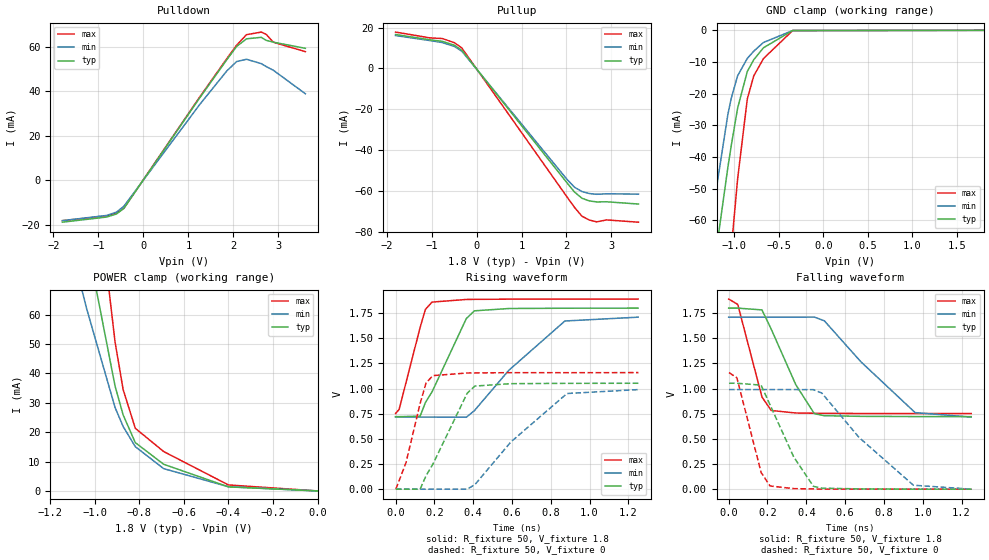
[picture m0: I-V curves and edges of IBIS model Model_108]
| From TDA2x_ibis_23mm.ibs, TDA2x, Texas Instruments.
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| Model based on original model for DDR_SEIOPB_H
|   Sub model SR111_DRV34_1P8
[model]   Model_108
|[Description]  [1.8V-I/O-X-X]
|   , ,
|[Input Load]
|[Output Drive]
|Voltage   1.8V
|Mode   I/O
Model_type   I/O
Polarity   Non-Inverting
Enable   Active-Low
Vinl =  0.775
Vinh =  1.025
Cref =  15.0000pF
Rref =  100.0000M
Vref =  0V
Vmeas =  0.9
C_comp   2p   2p   2p
[Model Spec]
Vinl   0.78   0.735   0.825
Vinh   1.02   0.975   1.065
[Receiver Thresholds]
Tslew_ac = 0.5n
Vth= 0.9
Vth_max= 0.945
Vth_min= 0.81
Vinh_ac= 0.2
Vinh_dc= 0.125
Vinl_ac= -0.2
Vinl_dc= -0.125
[Temperature Range]   25   125   -40
[Voltage Range]   1.8   1.71   1.89
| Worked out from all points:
|   slope of the pulldown table from 0 to 0.27 V, typ, clamps not added: 33.3 ohm
|   slope of the pullup table from 0 to 0.27 V, typ, clamps not added: 35.5 ohm
|   GND clamp passes 1 mA (typ) near -0.48 V on its own axis
|   POWER clamp passes 1 mA (typ) near -0.38 V on its own axis
|   rising waveform, R_fixture 50, V_fixture 1.8: 20-80 % time 172ps typ, 369ps min, 90.1ps max; typ from 0.721 V to 1.8 V
|   rising waveform, R_fixture 50, V_fixture 0: 20-80 % time 172ps typ, 367ps min, 89.3ps max; typ from 0 V to 1.05 V
|   falling waveform, R_fixture 50, V_fixture 1.8: 20-80 % time 157ps typ, 329ps min, 88.6ps max; typ from 1.8 V to 0.721 V
|   falling waveform, R_fixture 50, V_fixture 0: 20-80 % time 162ps typ, 340ps min, 88.6ps max; typ from 1.05 V to 0 V
[POWER_clamp]
-1.8V     464.6mA    344.4mA    740.8mA
-1.273V   197mA      143.3mA    314.4mA
-1.164V   144mA      104.2mA    229mA
-1.145V   135.3mA    97.86mA    215mA
-1.055V   93.25mA    67.59mA    146.5mA
-1.036V   85.18mA    61.89mA    133.3mA
-909.1mV  35.72mA    28.41mA    50.73mA
-872.7mV  25.87mA    21.94mA    34.5mA
-818.2mV  16.45mA    15.08mA    21.33mA
-690.9mV  9.084mA    7.592mA    13.42mA
-400mV    1.38mA     1.43mA     2.039mA
0V        227.3nA    761nA      1.176uA
[Pulldown]
-1.8V     -18.96mA   -18.25mA   -18.29mA
-818.2mV  -16.64mA   -15.93mA   -16.11mA
-600mV    -15.26mA   -14.42mA   -14.86mA
-436.4mV  -12.77mA   -11.85mA   -12.76mA
1.255V    37.14mA    34.14mA    37.53mA
1.855V    54.25mA    49.2mA     54.74mA
2.073V    60.22mA    53.41mA    60.8mA
2.291V    63.64mA    54.44mA    65.5mA
2.618V    64.32mA    52.48mA    66.68mA
2.727V    62.98mA    51.19mA    65.69mA
2.891V    62.13mA    49.45mA    62.08mA
3.6V      59.37mA    38.9mA     57.88mA
[Pullup]
-1.8V     16.66mA    16.14mA    17.84mA
-1.036V   14.05mA    13.69mA    15mA
-763.6mV  13.33mA    12.72mA    14.68mA
-490.9mV  11.4mA     10.78mA    12.65mA
-327.3mV  8.923mA    8.488mA    10.05mA
2.018V    -56.27mA   -54.56mA   -63.19mA
2.182V    -60.67mA   -58.29mA   -68.22mA
2.345V    -63.65mA   -60.35mA   -72.46mA
2.509V    -64.94mA   -61.33mA   -74.33mA
2.673V    -65.44mA   -61.69mA   -75.21mA
2.891V    -65.36mA   -61.45mA   -74.26mA
3.6V      -66.47mA   -61.61mA   -75.37mA
[GND_clamp]
-1.8V     -200.8mA   -187.9mA   -345.9mA
-1.327V   -95.75mA   -76.22mA   -171.1mA
-1.255V   -80.19mA   -60.47mA   -144.9mA
-1.218V   -72.53mA   -52.92mA   -131.9mA
-1.073V   -43.32mA   -26.59mA   -81.54mA
-1.036V   -36.61mA   -21.6mA    -69.55mA
-963.6mV  -24.61mA   -14.37mA   -47.01mA
-854.5mV  -12.98mA   -8.864mA   -21.66mA
-781.8mV  -9.263mA   -6.573mA   -14.36mA
-672.7mV  -5.498mA   -3.827mA   -8.897mA
-345.5mV  -48.81uA   -73.08uA   -79.37uA
1.8V      227.3nA    3.986uA    988nA
[Ramp]
dV/dt_f 0.64819116/0.15732551n 0.59696121/0.329717n  0.68332087/88.701046p
dV/dt_r 0.63301156/0.17256637n 0.59531836/0.36728602n 0.69620168/89.53648p
R_load = 50
[Rising Waveform]
R_fixture = 50
V_fixture = 1.8
V_fixture_min = 1.71
V_fixture_max = 1.89
0s        720.8mV    716.7mV    752.7mV
18.38ps   720.9mV    716.6mV    792.5mV
126.7ps   725.8mV    716.6mV    1.608V
154ps     862mV      716.6mV    1.788V
188.5ps   969mV      716.7mV    1.86V
364.7ps   1.696V     715mV      1.886V
406.5ps   1.773V     781.1mV    1.887V
583.3ps   1.796V     1.181V     1.889V
872.7ps   1.799V     1.672V     1.89V
1.25ns    1.8V       1.71V      1.89V
[Rising Waveform]
R_fixture = 50
V_fixture = 0
V_fixture_min = 0
V_fixture_max = 0
1.558ps   0V         0V         0V
53.63ps   0V         0V         261.6mV
126.7ps   0V         0V         852mV
157.1ps   133.2mV    0V         1.055V
192.1ps   247.2mV    0V         1.129V
369.1ps   953.6mV    0V         1.155V
408.7ps   1.025V     44.57mV    1.156V
594.1ps   1.049V     469.1mV    1.158V
883.6ps   1.052V     951mV      1.158V
1.252ns   1.053V     990.1mV    1.159V
[Falling Waveform]
R_fixture = 50
V_fixture = 1.8
V_fixture_min = 1.71
V_fixture_max = 1.89
0s        1.8V       1.71V      1.89V
46.64ps   1.8V       1.71V      1.837V
171.6ps   1.782V     1.71V      916.2mV
219.3ps   1.591V     1.71V      782.2mV
345.6ps   1.04V      1.71V      757.3mV
441.3ps   750.7mV    1.711V     754.7mV
492.9ps   730.5mV    1.674V     753.9mV
681.1ps   723.9mV    1.267V     752.4mV
960.8ps   721.8mV    761.1mV    751.9mV
1.25ns    720.8mV    716.7mV    751.8mV
[Falling Waveform]
R_fixture = 50
V_fixture = 0
V_fixture_min = 0
V_fixture_max = 0
1.558ps   1.053V     990.1mV    1.159V
42.33ps   1.053V     990.1mV    1.107V
167.2ps   1.034V     990.1mV    165.9mV
213.4ps   837.4mV    990mV      31.64mV
335.6ps   318.8mV    989.8mV    5.172mV
436.8ps   28.22mV    989.4mV    2.215mV
480.2ps   10.24mV    955.2mV    0V
671.6ps   2.641mV    514.7mV    0V
952.2ps   0V         39.18mV    0V
1.252ns   0V         0V         0V
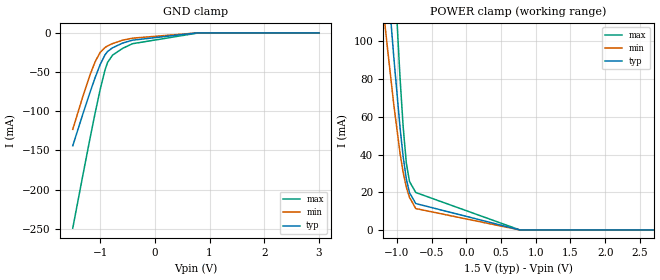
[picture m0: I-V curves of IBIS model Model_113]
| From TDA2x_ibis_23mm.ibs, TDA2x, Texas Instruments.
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| Model based on original model for DDR_SEIOPB_H
|   Sub model DDR3_ODT_120_1P5
[model]   Model_113
|[Description]  [1.5V-INPUT-X-X]
|   , ,
|[Input Load]
|[Output Drive]
|Voltage   1.5V
|Mode   INPUT
Model_type   Input
Polarity   Non-Inverting
Vinl = 0.65
Vinh = 0.85
C_comp   1p   0.5p   1.75p
[Receiver Thresholds]
Tslew_ac = 0.5n
Vth= 0.75
Vth_max= 0.7875
Vth_min= 0.675
Vinh_ac= 0.175
Vinh_dc= 0.1
Vinl_ac= -0.175
Vinl_dc= -0.1
[Temperature Range]   25   125   -40
[Voltage Range]   1.5   1.425   1.575
[POWER_clamp]
-1.5V     313.5mA    230.7mA    499.5mA
-1.273V   199.8mA    145.4mA    317.8mA
-1.182V   155.6mA    112.6mA    246.7mA
-1.136V   133.9mA    96.79mA    211.7mA
-1.045V   92.18mA    66.78mA    143.6mA
-954.5mV  54.51mA    40.82mA    81.12mA
-909.1mV  38.89mA    30.54mA    54.77mA
-863.6mV  27.13mA    22.75mA    35.57mA
-818.2mV  19.83mA    17.32mA    25.73mA
-727.3mV  14.01mA    11.35mA    19.86mA
772.7mV   0A         0A         0A
3V        0A         0A         0A
[GND_clamp]
-1.5V     -144mA     -123.1mA   -249.1mA
-1.318V   -104.1mA   -81.62mA   -182.5mA
-1.182V   -75.27mA   -53.07mA   -133.7mA
-1.091V   -57.04mA   -36.82mA   -102.3mA
-1V       -40.52mA   -24.95mA   -72.54mA
-909.1mV  -27.83mA   -18.53mA   -46.98mA
-863.6mV  -23.8mA    -16.61mA   -37.72mA
-772.7mV  -19.02mA   -13.67mA   -28.41mA
-590.9mV  -13.06mA   -9.333mA   -19.82mA
-409.1mV  -9.294mA   -6.738mA   -13.81mA
772.7mV   0A         0A         -328.7uA
3V        0A         0A         0A
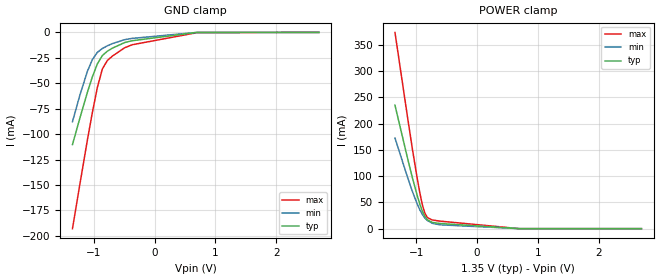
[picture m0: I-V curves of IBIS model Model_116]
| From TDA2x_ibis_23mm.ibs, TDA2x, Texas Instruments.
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| Model based on original model for DDR_SEIOPB_H
|   Sub model DDR3L_ODT_120_1P35
[model]   Model_116
|[Description]  [1.35V-INPUT-X-X]
|   , ,
|[Input Load]
|[Output Drive]
|Voltage   1.35V
|Mode   INPUT
Model_type   Input
Polarity   Non-Inverting
Vinl = 0.585
Vinh = 0.765
C_comp   1p   0.5p   1.75p
[Receiver Thresholds]
Tslew_ac = 5n
Vth= 0.675
Vth_max= 0.709
Vth_min= 0.608
Vinh_ac= 0.175
Vinh_dc= 0.1
Vinl_ac= -0.175
Vinl_dc= -0.1
[Temperature Range]   25   125   -40
[Voltage Range]   1.35   1.2825   1.4175
[POWER_clamp]
-1.35V    235.2mA    172.7mA    373.9mA
-1.145V   135mA      98.41mA    213.4mA
-1.064V   97.08mA    70.95mA    151.9mA
-981.8mV  61.96mA    46.31mA    94.02mA
-940.9mV  46.38mA    35.8mA     67.88mA
-900mV    33.1mA     27.05mA    45.49mA
-859.1mV  23.18mA    20.38mA    29.5mA
-818.2mV  16.93mA    15.6mA     21.23mA
-736.4mV  11.84mA    10.12mA    16.5mA
-613.6mV  9.897mA    7.359mA    14.38mA
695.5mV   0A         0A         26.81uA
2.7V      0A         0A         0A
[GND_clamp]
-1.35V    -110.3mA   -87.86mA   -193mA
-1.227V   -84.01mA   -61.44mA   -148.8mA
-1.105V   -58.98mA   -38.34mA   -105.9mA
-1.023V   -43.7mA    -26.73mA   -78.71mA
-940.9mV  -30.94mA   -19.63mA   -54.14mA
-859.1mV  -22.78mA   -15.82mA   -35.96mA
-777.3mV  -18.52mA   -13.21mA   -27.69mA
-695.5mV  -15.53mA   -11.04mA   -23.38mA
-490.9mV  -9.942mA   -7.113mA   -15.05mA
-368.2mV  -8.2mA     -5.879mA   -12.14mA
695.5mV   0A         0A         -267.5uA
2.7V      0A         0A         0A
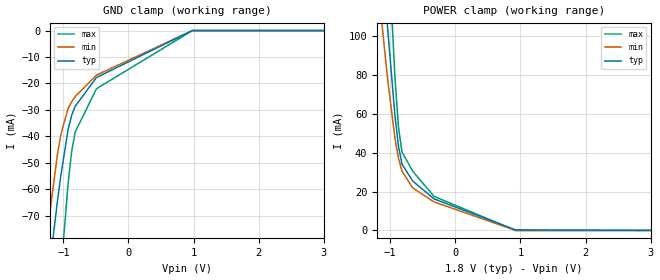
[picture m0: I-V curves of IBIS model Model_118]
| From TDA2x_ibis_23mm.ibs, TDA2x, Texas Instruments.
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| Model based on original model for DDR_SEIOPB_H
|   Sub model DDR2_ODT_80_1P8
[model]   Model_118
|[Description]  [1.8V-INPUT-X-X]
|   , ,
|[Input Load]
|[Output Drive]
|Voltage   1.8V
|Mode   INPUT
Model_type   Input
Polarity   Non-Inverting
Vinl =  0.775
Vinh =  1.025
C_comp   1p   0.5p   1.75p
[Receiver Thresholds]
Tslew_ac = 0.5n
Vth= 0.9
Vth_max= 0.945
Vth_min= 0.81
Vinh_ac= 0.2
Vinh_dc= 0.125
Vinl_ac= -0.2
Vinl_dc= -0.125
[Temperature Range]   25   125   -40
[Voltage Range]   1.8   1.71   1.89
[POWER_clamp]
-1.8V     482.4mA    357.9mA    759.4mA
-1.255V   205.7mA    151.4mA    318.3mA
-1.145V   152.9mA    112.8mA    233.2mA
-1.091V   127.3mA    94.41mA    191.7mA
-1.036V   102.6mA    76.98mA    151.4mA
-927.3mV  59.11mA    47.51mA    78.99mA
-872.7mV  43.45mA    37.29mA    53.09mA
-818.2mV  34.12mA    30.5mA     40.26mA
-654.5mV  25.4mA     21.91mA    30.49mA
-327.3mV  16.24mA    14.7mA     17.54mA
927.3mV   295.1uA    0A         0A
3.6V      0A         0A         0A
[GND_clamp]
-1.8V     -219.3mA   -205.9mA   -368.7mA
-1.364V   -121.8mA   -102mA     -206.3mA
-1.309V   -110mA     -89.84mA   -186.4mA
-1.255V   -98.27mA   -78.06mA   -166.7mA
-1.091V   -64.72mA   -46.91mA   -109.1mA
-1.036V   -54.5mA    -39.11mA   -90.88mA
-927.3mV  -37.55mA   -29.51mA   -58.13mA
-872.7mV  -32.11mA   -26.95mA   -45.87mA
-818.2mV  -28.67mA   -24.98mA   -38.4mA
-490.9mV  -17.74mA   -16.84mA   -21.99mA
981.8mV   0A         0A         0A
3.6V      0A         0A         0A
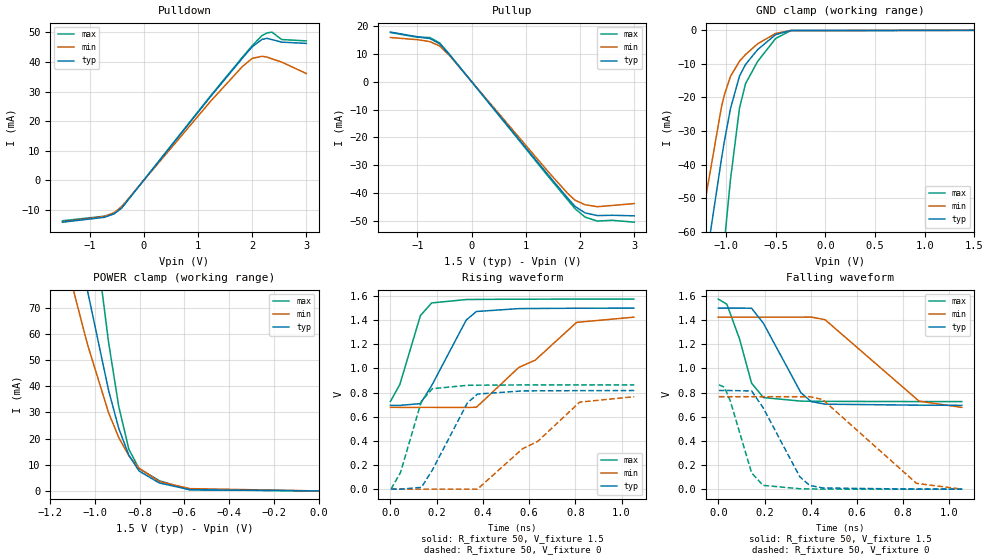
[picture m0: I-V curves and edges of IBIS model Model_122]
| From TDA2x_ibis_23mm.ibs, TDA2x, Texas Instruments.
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| Model based on original model for DDR_SEIOPB_H
|   Sub model SR101_DRV40_1P5
[model]   Model_122
|[Description]  [1.5V-I/O-X-X]
|   , ,
|[Input Load]
|[Output Drive]
|Voltage   1.5V
|Mode   I/O
Model_type   I/O
Polarity   Non-Inverting
Enable   Active-Low
Vinl =  0.65
Vinh =  0.85
Cref =  15.0000pF
Rref =  100.0000M
Vref =  0V
Vmeas =  0.75
C_comp   2p   2p   2p
[Model Spec]
Vinl   0.65   0.6125   0.6875
Vinh   0.85   0.8125   0.8875
[Receiver Thresholds]
Tslew_ac = 0.5n
Vth= 0.75
Vth_max= 0.7875
Vth_min= 0.675
Vinh_ac= 0.175
Vinh_dc= 0.1
Vinl_ac= -0.175
Vinl_dc= -0.1
[Temperature Range]   25   125   -40
[Voltage Range]   1.5   1.425   1.575
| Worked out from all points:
|   slope of the pulldown table from 0 to 0.225 V, typ, clamps not added: 43 ohm
|   slope of the pullup table from 0 to 0.225 V, typ, clamps not added: 41.7 ohm
|   GND clamp passes 1 mA (typ) near -0.48 V on its own axis
|   POWER clamp passes 1 mA (typ) near -0.62 V on its own axis
|   rising waveform, R_fixture 50, V_fixture 1.5: 20-80 % time 136ps typ, 308ps min, 78.1ps max; typ from 0.695 V to 1.5 V
|   rising waveform, R_fixture 50, V_fixture 0: 20-80 % time 135ps typ, 299ps min, 78ps max; typ from 0 V to 0.817 V
|   falling waveform, R_fixture 50, V_fixture 1.5: 20-80 % time 134ps typ, 278ps min, 77.5ps max; typ from 1.5 V to 0.695 V
|   falling waveform, R_fixture 50, V_fixture 0: 20-80 % time 135ps typ, 288ps min, 77.9ps max; typ from 0.817 V to 0 V
[POWER_clamp]
-1.5V     302.8mA    223.9mA    484.4mA
-1.242V   174.3mA    127.3mA    279.1mA
-1.136V   123.3mA    89.68mA    196.8mA
-1.045V   81.65mA    59.62mA    128.8mA
-1.03V    75mA       54.92mA    117.8mA
-939.4mV  38.44mA    29.91mA    56.84mA
-893.9mV  23.93mA    20.41mA    32.31mA
-848.5mV  13.61mA    13.43mA    15.91mA
-803mV    7.623mA    8.663mA    8.564mA
-712.1mV  3.022mA    3.561mA    3.877mA
-575.8mV  470.5uA    872uA      449uA
0V        112.6nA    435.6nA    613.8nA
[Pulldown]
-1.5V     -14.18mA   -14.05mA   -13.7mA
-727.3mV  -12.54mA   -12.27mA   -12.15mA
-545.5mV  -11.35mA   -10.95mA   -11.1mA
-409.1mV  -9.378mA   -8.925mA   -9.416mA
1.227V    28.16mA    26.58mA    28.43mA
1.818V    41.23mA    38.42mA    41.56mA
2V        45.11mA    41.2mA     45.49mA
2.182V    47.62mA    41.92mA    48.94mA
2.273V    47.99mA    41.65mA    49.78mA
2.364V    47.57mA    41.06mA    50.1mA
2.545V    46.7mA     39.96mA    47.58mA
3V        46.28mA    36.09mA    47.12mA
[Pullup]
-1.5V     17.97mA    16.01mA    17.82mA
-1V       16.28mA    15.23mA    16.1mA
-772.7mV  15.66mA    14.54mA    16.02mA
-590.9mV  13.75mA    12.97mA    14.08mA
-409.1mV  9.799mA    9.534mA    9.955mA
1.409V    -33.42mA   -32.26mA   -33.94mA
1.773V    -41.87mA   -40.19mA   -42.52mA
1.909V    -44.87mA   -42.6mA    -45.68mA
2.091V    -47.15mA   -44.23mA   -48.65mA
2.318V    -48.13mA   -44.93mA   -50.11mA
2.591V    -48.02mA   -44.49mA   -49.82mA
3V        -48.22mA   -43.8mA    -50.51mA
[GND_clamp]
-1.5V     -133.6mA   -115.7mA   -234.3mA
-1.288V   -87.29mA   -67.59mA   -156.8mA
-1.197V   -68.11mA   -48.64mA   -124.4mA
-1.045V   -38.25mA   -22.77mA   -72.51mA
-1.015V   -32.88mA   -19.1mA    -62.74mA
-954.5mV  -23.3mA    -13.72mA   -44.4mA
-863.6mV  -13.6mA    -9.192mA   -23.11mA
-803mV    -10.18mA   -7.193mA   -15.89mA
-681.8mV  -5.771mA   -4.027mA   -9.287mA
-500mV    -1.264mA   -914.7uA   -2.429mA
-348.5mV  -52.39uA   -75.11uA   -85.87uA
1.5V      112.6nA    528.1nA    514.5nA
[Ramp]
dV/dt_f 0.48371638/0.1344601n 0.44929255/0.27899089n 0.51008323/77.587251p
dV/dt_r 0.49174227/0.13539252n 0.46153752/0.30103568n 0.51970717/78.162105p
R_load = 50
[Rising Waveform]
R_fixture = 50
V_fixture = 1.5
V_fixture_min = 1.425
V_fixture_max = 1.575
0s        694.7mV    677.7mV    726.3mV
40.92ps   694mV      677.6mV    867.3mV
129.9ps   708.9mV    677.6mV    1.438V
178.6ps   858.2mV    677.7mV    1.543V
328ps     1.401V     676.8mV    1.571V
372.1ps   1.472V     678.6mV    1.572V
555.7ps   1.496V     1.009V     1.574V
626.7ps   1.497V     1.069V     1.574V
805.6ps   1.499V     1.382V     1.575V
1.053ns   1.5V       1.425V     1.575V
[Rising Waveform]
R_fixture = 50
V_fixture = 0
V_fixture_min = 0
V_fixture_max = 0
2.617ps   0V         0V         0V
43.65ps   0V         0V         137.9mV
134.3ps   15.11mV    0V         728.9mV
181.2ps   156.8mV    0V         832.2mV
332.5ps   712.7mV    0V         860.5mV
376.6ps   787.9mV    0V         861.5mV
571.4ps   814.1mV    334.9mV    863.4mV
636.5ps   814.9mV    394.4mV    863.6mV
819ps     816.1mV    721.2mV    863.9mV
1.055ns   817.1mV    766.1mV    864.1mV
[Falling Waveform]
R_fixture = 50
V_fixture = 1.5
V_fixture_min = 1.425
V_fixture_max = 1.575
0s        1.5V       1.425V     1.575V
37ps      1.5V       1.425V     1.532V
91.62ps   1.5V       1.425V     1.246V
144ps     1.499V     1.425V     877.9mV
195.5ps   1.373V     1.425V     758.8mV
357.2ps   799.6mV    1.425V     729.5mV
401.2ps   726mV      1.426V     728.5mV
461.8ps   704.2mV    1.404V     727.5mV
868.6ps   695.8mV    728.9mV    725.6mV
1.053ns   694.7mV    677.7mV    725.4mV
[Falling Waveform]
R_fixture = 50
V_fixture = 0
V_fixture_min = 0
V_fixture_max = 0
2.617ps   817.1mV    766.1mV    864.1mV
26.17ps   817.2mV    766.1mV    845.5mV
51.72ps   817.2mV    766.1mV    731.9mV
144.1ps   813.5mV    766.2mV    135mV
193.2ps   677.1mV    766.1mV    31.72mV
352.5ps   102.6mV    766mV      3.47mV
395.2ps   31.13mV    766.5mV    2.395mV
451.1ps   10.07mV    742.9mV    0V
857.4ps   0V         48.03mV    0V
1.055ns   0V         0V         0V
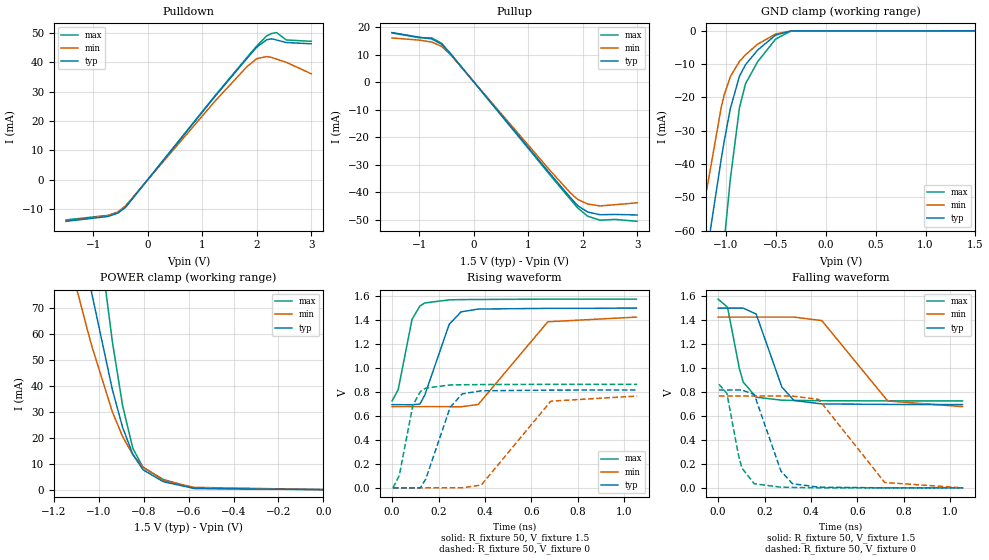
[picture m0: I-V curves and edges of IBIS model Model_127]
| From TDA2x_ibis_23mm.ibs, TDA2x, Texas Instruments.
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| Model based on original model for DDR_SEIOPB_H
|   Sub model SR000_DRV40_1P5
[model]   Model_127
|[Description]  [1.5V-I/O-X-X]
|   , ,
|[Input Load]
|[Output Drive]
|Voltage   1.5V
|Mode   I/O
Model_type   I/O
Polarity   Non-Inverting
Enable   Active-Low
Vinl =  0.65
Vinh =  0.85
Cref =  15.0000pF
Rref =  100.0000M
Vref =  0V
Vmeas =  0.75
C_comp   2p   2p   2p
[Model Spec]
Vinl   0.65   0.6125   0.6875
Vinh   0.85   0.8125   0.8875
[Receiver Thresholds]
Tslew_ac = 0.5n
Vth= 0.75
Vth_max= 0.7875
Vth_min= 0.675
Vinh_ac= 0.175
Vinh_dc= 0.1
Vinl_ac= -0.175
Vinl_dc= -0.1
[Temperature Range]   25   125   -40
[Voltage Range]   1.5   1.425   1.575
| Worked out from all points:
|   slope of the pulldown table from 0 to 0.225 V, typ, clamps not added: 43 ohm
|   slope of the pullup table from 0 to 0.225 V, typ, clamps not added: 41.7 ohm
|   GND clamp passes 1 mA (typ) near -0.48 V on its own axis
|   POWER clamp passes 1 mA (typ) near -0.62 V on its own axis
|   rising waveform, R_fixture 50, V_fixture 1.5: 20-80 % time 82.9ps typ, 189ps min, 50.6ps max; typ from 0.695 V to 1.5 V
|   rising waveform, R_fixture 50, V_fixture 0: 20-80 % time 83ps typ, 185ps min, 50.5ps max; typ from 0 V to 0.817 V
|   falling waveform, R_fixture 50, V_fixture 1.5: 20-80 % time 83.7ps typ, 176ps min, 52.3ps max; typ from 1.5 V to 0.695 V
|   falling waveform, R_fixture 50, V_fixture 0: 20-80 % time 83.6ps typ, 179ps min, 51.7ps max; typ from 0.817 V to 0 V
[POWER_clamp]
-1.5V     302.8mA    223.9mA    484.4mA
-1.242V   174.3mA    127.3mA    279.1mA
-1.136V   123.3mA    89.68mA    196.8mA
-1.045V   81.65mA    59.62mA    128.8mA
-1.03V    75mA       54.92mA    117.8mA
-939.4mV  38.44mA    29.91mA    56.84mA
-893.9mV  23.93mA    20.41mA    32.31mA
-848.5mV  13.61mA    13.43mA    15.91mA
-803mV    7.623mA    8.663mA    8.564mA
-712.1mV  3.022mA    3.561mA    3.877mA
-575.8mV  470.5uA    872uA      449uA
0V        112.6nA    435.6nA    613.8nA
[Pulldown]
-1.5V     -14.18mA   -14.05mA   -13.7mA
-727.3mV  -12.54mA   -12.27mA   -12.15mA
-545.5mV  -11.35mA   -10.95mA   -11.1mA
-409.1mV  -9.378mA   -8.925mA   -9.416mA
1.227V    28.16mA    26.58mA    28.43mA
1.818V    41.23mA    38.42mA    41.56mA
2V        45.11mA    41.2mA     45.49mA
2.182V    47.62mA    41.92mA    48.94mA
2.273V    47.99mA    41.65mA    49.78mA
2.364V    47.57mA    41.06mA    50.1mA
2.545V    46.7mA     39.96mA    47.58mA
3V        46.28mA    36.09mA    47.12mA
[Pullup]
-1.5V     17.97mA    16.01mA    17.82mA
-1V       16.28mA    15.23mA    16.1mA
-772.7mV  15.66mA    14.54mA    16.02mA
-590.9mV  13.75mA    12.97mA    14.08mA
-409.1mV  9.799mA    9.534mA    9.955mA
1.409V    -33.42mA   -32.26mA   -33.94mA
1.773V    -41.87mA   -40.19mA   -42.52mA
1.909V    -44.87mA   -42.6mA    -45.68mA
2.091V    -47.15mA   -44.23mA   -48.65mA
2.318V    -48.13mA   -44.93mA   -50.11mA
2.591V    -48.02mA   -44.49mA   -49.82mA
3V        -48.22mA   -43.8mA    -50.51mA
[GND_clamp]
-1.5V     -133.6mA   -115.7mA   -234.3mA
-1.288V   -87.29mA   -67.59mA   -156.8mA
-1.197V   -68.11mA   -48.64mA   -124.4mA
-1.045V   -38.25mA   -22.77mA   -72.51mA
-1.015V   -32.88mA   -19.1mA    -62.74mA
-954.5mV  -23.3mA    -13.72mA   -44.4mA
-863.6mV  -13.6mA    -9.192mA   -23.11mA
-803mV    -10.18mA   -7.193mA   -15.89mA
-681.8mV  -5.771mA   -4.027mA   -9.287mA
-500mV    -1.264mA   -914.7uA   -2.429mA
-348.5mV  -52.39uA   -75.11uA   -85.87uA
1.5V      112.6nA    528.1nA    514.5nA
[Ramp]
dV/dt_f 0.48364903/83.821371p 0.44912812/0.17636424n 0.50998143/52.340509p
dV/dt_r 0.49180675/83.243552p 0.46129703/0.18594643n 0.51998788/50.619034p
R_load = 50
[Rising Waveform]
R_fixture = 50
V_fixture = 1.5
V_fixture_min = 1.425
V_fixture_max = 1.575
0s        694.7mV    677.7mV    726mV
26.2ps    694mV      677.6mV    819.5mV
86ps      693.6mV    677.6mV    1.407V
119.7ps   699.3mV    677.6mV    1.517V
140.8ps   774mV      677.6mV    1.543V
246.1ps   1.365V     677.4mV    1.569V
297.3ps   1.469V     676.9mV    1.571V
371.2ps   1.492V     696mV      1.572V
671ps     1.498V     1.386V     1.575V
1.053ns   1.5V       1.425V     1.575V
[Rising Waveform]
R_fixture = 50
V_fixture = 0
V_fixture_min = 0
V_fixture_max = 0
3.612ps   0V         0V         0V
30.99ps   0V         0V         103.4mV
89.21ps   0V         0V         688.8mV
122ps     0V         0V         803.5mV
144.9ps   72.96mV    0V         832.7mV
250.3ps   672.5mV    0V         858.6mV
302.1ps   784.8mV    0V         860.5mV
384.4ps   810mV      23.87mV    862mV
683.8ps   815.7mV    723.3mV    863.8mV
1.056ns   817.1mV    766.1mV    864.1mV
[Falling Waveform]
R_fixture = 50
V_fixture = 1.5
V_fixture_min = 1.425
V_fixture_max = 1.575
0s        1.5V       1.425V     1.575V
40.52ps   1.5V       1.425V     1.507V
91.44ps   1.5V       1.425V     996.8mV
107.8ps   1.5V       1.425V     883.5mV
163.8ps   1.451V     1.425V     756.6mV
274.7ps   841.1mV    1.425V     731.6mV
327ps     729mV      1.425V     729.6mV
446.7ps   700.5mV    1.396V     727.3mV
730.7ps   696.3mV    725mV      725.7mV
1.053ns   694.7mV    677.7mV    725.4mV
[Falling Waveform]
R_fixture = 50
V_fixture = 0
V_fixture_min = 0
V_fixture_max = 0
3.612ps   817.1mV    766.1mV    864.1mV
37.75ps   817.3mV    766.2mV    787.9mV
87.13ps   816.8mV    766.2mV    278.2mV
102.3ps   816.8mV    766.2mV    165.9mV
155.8ps   779.5mV    766.2mV    33.95mV
270.3ps   141.5mV    766.2mV    5.695mV
320.4ps   34.44mV    765.9mV    3.63mV
433.6ps   6.028mV    738.2mV    0V
718.1ps   0V         44.47mV    0V
1.056ns   0V         0V         0V
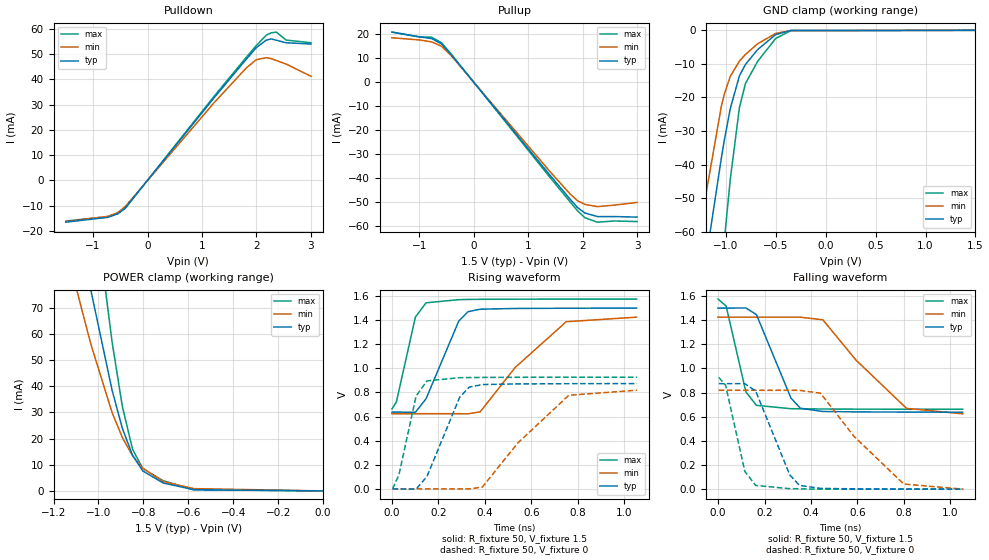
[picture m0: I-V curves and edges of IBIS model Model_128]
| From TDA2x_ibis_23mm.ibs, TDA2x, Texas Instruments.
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| Model based on original model for DDR_SEIOPB_H
|   Sub model SR011_DRV34_1P5
[model]   Model_128
|[Description]  [1.5V-I/O-X-X]
|   , ,
|[Input Load]
|[Output Drive]
|Voltage   1.5V
|Mode   I/O
Model_type   I/O
Polarity   Non-Inverting
Enable   Active-Low
Vinl =  0.65
Vinh =  0.85
Cref =  15.0000pF
Rref =  100.0000M
Vref =  0V
Vmeas =  0.75
C_comp   2p   2p   2p
[Model Spec]
Vinl   0.65   0.6125   0.6875
Vinh   0.85   0.8125   0.8875
[Receiver Thresholds]
Tslew_ac = 0.5n
Vth= 0.75
Vth_max= 0.7875
Vth_min= 0.675
Vinh_ac= 0.175
Vinh_dc= 0.1
Vinl_ac= -0.175
Vinl_dc= -0.1
[Temperature Range]   25   125   -40
[Voltage Range]   1.5   1.425   1.575
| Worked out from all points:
|   slope of the pulldown table from 0 to 0.225 V, typ, clamps not added: 36.8 ohm
|   slope of the pullup table from 0 to 0.225 V, typ, clamps not added: 35.8 ohm
|   GND clamp passes 1 mA (typ) near -0.48 V on its own axis
|   POWER clamp passes 1 mA (typ) near -0.62 V on its own axis
|   rising waveform, R_fixture 50, V_fixture 1.5: 20-80 % time 112ps typ, 267ps min, 61.5ps max; typ from 0.637 V to 1.5 V
|   rising waveform, R_fixture 50, V_fixture 0: 20-80 % time 111ps typ, 260ps min, 61.6ps max; typ from 0 V to 0.874 V
|   falling waveform, R_fixture 50, V_fixture 1.5: 20-80 % time 111ps typ, 245ps min, 62.9ps max; typ from 1.5 V to 0.637 V
|   falling waveform, R_fixture 50, V_fixture 0: 20-80 % time 111ps typ, 250ps min, 62.6ps max; typ from 0.874 V to 0 V
[POWER_clamp]
-1.5V     302.8mA    223.9mA    484.4mA
-1.242V   174.3mA    127.3mA    279.1mA
-1.136V   123.3mA    89.68mA    196.8mA
-1.045V   81.65mA    59.62mA    128.8mA
-1.03V    75mA       54.92mA    117.8mA
-939.4mV  38.44mA    29.91mA    56.84mA
-893.9mV  23.93mA    20.41mA    32.31mA
-848.5mV  13.61mA    13.43mA    15.91mA
-803mV    7.623mA    8.663mA    8.564mA
-712.1mV  3.022mA    3.561mA    3.877mA
-575.8mV  470.5uA    872uA      449uA
0V        112.6nA    435.6nA    613.8nA
[Pulldown]
-1.5V     -16.54mA   -16.32mA   -16.11mA
-727.3mV  -14.62mA   -14.26mA   -14.29mA
-545.5mV  -13.24mA   -12.72mA   -13.05mA
-409.1mV  -10.94mA   -10.36mA   -11.07mA
1.227V    32.84mA    30.87mA    33.41mA
1.818V    48.09mA    44.61mA    48.84mA
2V        52.62mA    47.82mA    53.46mA
2.182V    55.55mA    48.58mA    57.5mA
2.273V    55.99mA    48.2mA     58.42mA
2.364V    55.5mA     47.46mA    58.71mA
2.545V    54.48mA    46.06mA    55.55mA
3V        54mA       41.23mA    54.49mA
[Pullup]
-1.5V     20.96mA    18.6mA     20.95mA
-1V       19mA       17.69mA    18.93mA
-772.7mV  18.26mA    16.89mA    18.84mA
-590.9mV  16.04mA    15.07mA    16.54mA
-409.1mV  11.43mA    11.07mA    11.7mA
1.409V    -38.97mA   -37.46mA   -39.88mA
1.773V    -48.83mA   -46.66mA   -49.96mA
1.909V    -52.33mA   -49.44mA   -53.68mA
2.045V    -54.57mA   -50.97mA   -56.55mA
2.273V    -56.03mA   -51.89mA   -58.38mA
2.591V    -56.03mA   -51.23mA   -57.86mA
3V        -56.26mA   -50.14mA   -58.12mA
[GND_clamp]
-1.5V     -133.6mA   -115.7mA   -234.3mA
-1.288V   -87.29mA   -67.59mA   -156.8mA
-1.197V   -68.11mA   -48.64mA   -124.4mA
-1.045V   -38.25mA   -22.77mA   -72.51mA
-1.015V   -32.88mA   -19.1mA    -62.74mA
-954.5mV  -23.3mA    -13.72mA   -44.4mA
-863.6mV  -13.6mA    -9.192mA   -23.11mA
-803mV    -10.18mA   -7.193mA   -15.89mA
-681.8mV  -5.771mA   -4.027mA   -9.287mA
-500mV    -1.264mA   -914.7uA   -2.429mA
-348.5mV  -52.39uA   -75.11uA   -85.87uA
1.5V      112.6nA    528.1nA    514.5nA
[Ramp]
dV/dt_f 0.51822132/0.11075306n 0.48137328/0.24542701n  0.5480301/62.972467p
dV/dt_r 0.52633839/0.11136384n  0.4935113/0.26182759n  0.5577269/61.70354p
R_load = 50
[Rising Waveform]
R_fixture = 50
V_fixture = 1.5
V_fixture_min = 1.425
V_fixture_max = 1.575
0s        637.3mV    624.3mV    663.2mV
19.08ps   637mV      624.2mV    720.4mV
101ps     635.7mV    624.2mV    1.425V
147ps     748.1mV    624.2mV    1.544V
287.6ps   1.392V     624.2mV    1.57V
327.2ps   1.47V      622.6mV    1.572V
379.8ps   1.491V     639.3mV    1.573V
530.2ps   1.497V     1.007V     1.574V
750.2ps   1.499V     1.387V     1.575V
1.053ns   1.5V       1.425V     1.575V
[Rising Waveform]
R_fixture = 50
V_fixture = 0
V_fixture_min = 0
V_fixture_max = 0
2.72ps    0V         0V         0V
30.07ps   0V         0V         116mV
104.1ps   -2.032mV   0V         770.9mV
150.9ps   103.2mV    0V         896.2mV
291.3ps   759.2mV    0V         922.9mV
332.6ps   844.5mV    0V         923.9mV
389.1ps   865.8mV    15.05mV    924.8mV
542ps     871.3mV    381.5mV    926mV
761.3ps   873mV      776.8mV    926.6mV
1.055ns   874.1mV    819mV      926.7mV
[Falling Waveform]
R_fixture = 50
V_fixture = 1.5
V_fixture_min = 1.425
V_fixture_max = 1.575
0s        1.5V       1.425V     1.575V
34.81ps   1.5V       1.425V     1.517V
120ps     1.501V     1.425V     805.4mV
165.3ps   1.446V     1.425V     694.5mV
313.6ps   755.3mV    1.425V     666.7mV
354ps     670.5mV    1.425V     665.7mV
451.1ps   643.5mV    1.403V     664.1mV
593.4ps   640.3mV    1.07V      663mV
810.9ps   638.5mV    669.7mV    662.4mV
1.053ns   637.3mV    624.3mV    662.3mV
[Falling Waveform]
R_fixture = 50
V_fixture = 0
V_fixture_min = 0
V_fixture_max = 0
2.72ps    874.1mV    819mV      926.7mV
32.34ps   874.3mV    819.1mV    861.6mV
115.4ps   874.2mV    819.1mV    146.6mV
162ps     812.9mV    819mV      31.16mV
308.5ps   119.1mV    818.9mV    3.932mV
350.1ps   31.47mV    818.9mV    2.764mV
441.1ps   6.279mV    795.1mV    0V
584.7ps   2.691mV    438.3mV    0V
799.3ps   0V         42.46mV    0V
1.055ns   0V         0V         0V
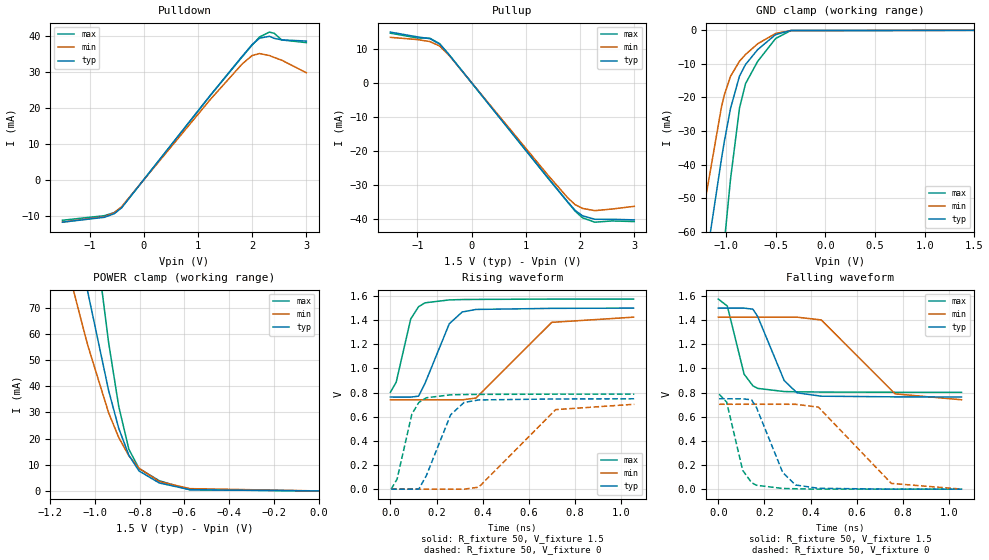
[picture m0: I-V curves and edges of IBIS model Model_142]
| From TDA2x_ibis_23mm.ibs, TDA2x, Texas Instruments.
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| Model based on original model for DDR_SEIOPB_H
|   Sub model SR001_DRV48_1P5
[model]   Model_142
|[Description]  [1.5V-I/O-X-X]
|   , ,
|[Input Load]
|[Output Drive]
|Voltage   1.5V
|Mode   I/O
Model_type   I/O
Polarity   Non-Inverting
Enable   Active-Low
Vinl =  0.65
Vinh =  0.85
Cref =  15.0000pF
Rref =  100.0000M
Vref =  0V
Vmeas =  0.75
C_comp   2p   2p   2p
[Model Spec]
Vinl   0.65   0.6125   0.6875
Vinh   0.85   0.8125   0.8875
[Receiver Thresholds]
Tslew_ac = 0.5n
Vth= 0.75
Vth_max= 0.7875
Vth_min= 0.675
Vinh_ac= 0.175
Vinh_dc= 0.1
Vinl_ac= -0.175
Vinl_dc= -0.1
[Temperature Range]   25   125   -40
[Voltage Range]   1.5   1.425   1.575
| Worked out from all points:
|   slope of the pulldown table from 0 to 0.225 V, typ, clamps not added: 51.5 ohm
|   slope of the pullup table from 0 to 0.225 V, typ, clamps not added: 50.1 ohm
|   GND clamp passes 1 mA (typ) near -0.48 V on its own axis
|   POWER clamp passes 1 mA (typ) near -0.62 V on its own axis
|   rising waveform, R_fixture 50, V_fixture 1.5: 20-80 % time 93ps typ, 229ps min, 56.2ps max; typ from 0.763 V to 1.5 V
|   rising waveform, R_fixture 50, V_fixture 0: 20-80 % time 93ps typ, 224ps min, 56.4ps max; typ from 0 V to 0.749 V
|   falling waveform, R_fixture 50, V_fixture 1.5: 20-80 % time 94.4ps typ, 212ps min, 58.3ps max; typ from 1.5 V to 0.763 V
|   falling waveform, R_fixture 50, V_fixture 0: 20-80 % time 94.2ps typ, 216ps min, 57.2ps max; typ from 0.749 V to 0 V
[POWER_clamp]
-1.5V     302.8mA    223.9mA    484.4mA
-1.242V   174.3mA    127.3mA    279.1mA
-1.136V   123.3mA    89.68mA    196.8mA
-1.045V   81.65mA    59.62mA    128.8mA
-1.03V    75mA       54.92mA    117.8mA
-939.4mV  38.44mA    29.91mA    56.84mA
-893.9mV  23.93mA    20.41mA    32.31mA
-848.5mV  13.61mA    13.43mA    15.91mA
-803mV    7.623mA    8.663mA    8.564mA
-712.1mV  3.022mA    3.561mA    3.877mA
-575.8mV  470.5uA    872uA      449uA
0V        112.6nA    435.6nA    613.8nA
[Pulldown]
-1.5V     -11.81mA   -11.79mA   -11.27mA
-727.3mV  -10.45mA   -10.3mA    -10mA
-545.5mV  -9.463mA   -9.189mA   -9.136mA
-409.1mV  -7.817mA   -7.49mA    -7.751mA
1.227V    23.47mA    22.31mA    23.4mA
1.818V    34.37mA    32.24mA    34.22mA
2V        37.61mA    34.55mA    37.45mA
2.136V    39.37mA    35.1mA     39.71mA
2.318V    39.9mA     34.55mA    41.07mA
2.409V    39.32mA    34mA       40.72mA
2.545V    38.91mA    33.26mA    38.88mA
3V        38.57mA    29.76mA    38.14mA
[Pullup]
-1.5V     14.98mA    13.43mA    14.66mA
-1V       13.57mA    12.78mA    13.25mA
-772.7mV  13.05mA    12.2mA     13.19mA
-590.9mV  11.46mA    10.89mA    11.59mA
-409.1mV  8.169mA    8.001mA    8.195mA
1.409V    -27.86mA   -27.07mA   -27.94mA
1.773V    -34.91mA   -33.72mA   -35mA
1.909V    -37.4mA    -35.72mA   -37.61mA
2.045V    -38.99mA   -36.82mA   -39.6mA
2.273V    -40.02mA   -37.48mA   -40.87mA
2.591V    -40.02mA   -37mA      -40.5mA
3V        -40.19mA   -36.21mA   -40.69mA
[GND_clamp]
-1.5V     -133.6mA   -115.7mA   -234.3mA
-1.288V   -87.29mA   -67.59mA   -156.8mA
-1.197V   -68.11mA   -48.64mA   -124.4mA
-1.045V   -38.25mA   -22.77mA   -72.51mA
-1.015V   -32.88mA   -19.1mA    -62.74mA
-954.5mV  -23.3mA    -13.72mA   -44.4mA
-863.6mV  -13.6mA    -9.192mA   -23.11mA
-803mV    -10.18mA   -7.193mA   -15.89mA
-681.8mV  -5.771mA   -4.027mA   -9.287mA
-500mV    -1.264mA   -914.7uA   -2.429mA
-348.5mV  -52.39uA   -75.11uA   -85.87uA
1.5V      112.6nA    528.1nA    514.5nA
[Ramp]
dV/dt_f  0.4424594/94.511921p 0.41132894/0.21290378n 0.46370359/58.357147p
dV/dt_r 0.45078989/93.298417p 0.42363717/0.22468686n 0.47383231/56.503683p
R_load = 50
[Rising Waveform]
R_fixture = 50
V_fixture = 1.5
V_fixture_min = 1.425
V_fixture_max = 1.575
0s        763.3mV    740.8mV    803.4mV
25ps      762.6mV    740.7mV    885.4mV
88.01ps   762.4mV    740.7mV    1.41V
122.2ps   770.9mV    740.7mV    1.512V
150.2ps   877.9mV    740.7mV    1.544V
255.2ps   1.371V     740.5mV    1.568V
311.1ps   1.468V     739.8mV    1.571V
370.7ps   1.489V     755.1mV    1.572V
698.8ps   1.498V     1.382V     1.575V
1.053ns   1.5V       1.425V     1.575V
[Rising Waveform]
R_fixture = 50
V_fixture = 0
V_fixture_min = 0
V_fixture_max = 0
3.404ps   0V         0V         0V
28.94ps   0V         0V         83.14mV
92.77ps   0V         0V         620.9mV
122.9ps   0V         0V         717.8mV
155.8ps   112.7mV    0V         757.5mV
261ps     616.6mV    0V         781.8mV
319.3ps   718.6mV    0V         783.9mV
382.6ps   739.3mV    16.46mV    785.2mV
715.6ps   747.4mV    659.1mV    787.1mV
1.056ns   748.7mV    703.3mV    787.3mV
[Falling Waveform]
R_fixture = 50
V_fixture = 1.5
V_fixture_min = 1.425
V_fixture_max = 1.575
0s        1.5V       1.425V     1.575V
39.05ps   1.5V       1.425V     1.517V
111.7ps   1.5V       1.425V     953.1mV
149.7ps   1.491V     1.425V     856.3mV
170.7ps   1.43V      1.425V     835mV
285.3ps   899.9mV    1.425V     808.8mV
340.6ps   798.4mV    1.425V     806.6mV
446ps     770.3mV    1.402V     804.6mV
765.4ps   764.8mV    789.6mV    802.8mV
1.053ns   763.3mV    740.8mV    802.5mV
[Falling Waveform]
R_fixture = 50
V_fixture = 0
V_fixture_min = 0
V_fixture_max = 0
3.404ps   748.7mV    703.3mV    787.3mV
36.15ps   748.9mV    703.3mV    721.2mV
105.5ps   748.4mV    703.3mV    156.4mV
144.1ps   740.2mV    703.4mV    53.92mV
165.3ps   676.1mV    703.3mV    32.35mV
278.8ps   138.7mV    703.3mV    5.736mV
334.2ps   34.7mV     703.1mV    3.405mV
433.2ps   7.152mV    680mV      0V
749.3ps   0V         47.56mV    0V
1.056ns   0V         0V         0V
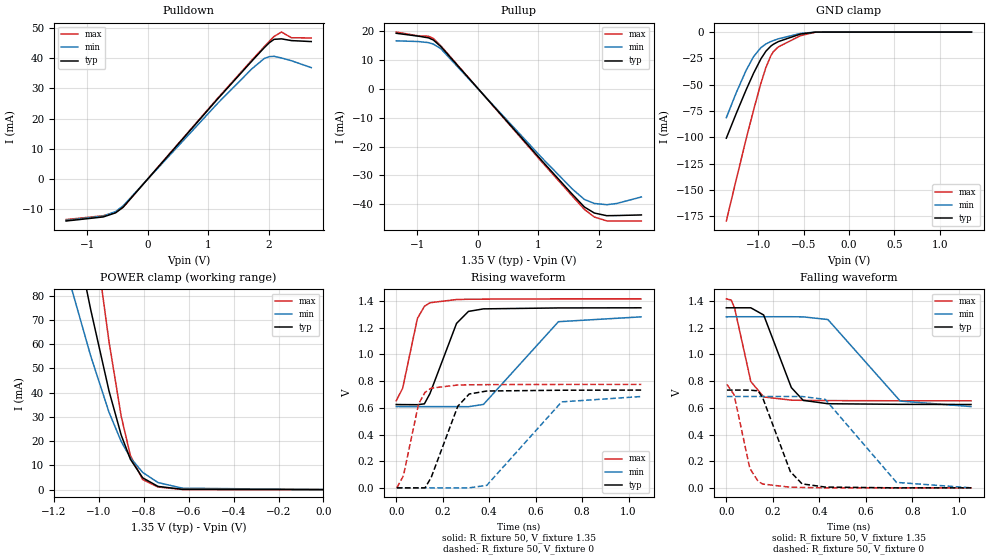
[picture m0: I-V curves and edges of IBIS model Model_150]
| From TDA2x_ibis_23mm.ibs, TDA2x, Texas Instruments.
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| Model based on original model for DDR_SEIOPB_H
|   Sub model SR001_DRV40_1P35
[model]   Model_150
|[Description]  [1.35V-I/O-X-X]
|   , ,
|[Input Load]
|[Output Drive]
|Voltage   1.35V
|Mode   I/O
Model_type   I/O
Polarity   Non-Inverting
Enable   Active-Low
Vinl =  0.585
Vinh =  0.765
Cref =  15.0000pF
Rref =  100.0000M
Vref =  0V
Vmeas =  0.675
C_comp   2p   2p   2p
[Model Spec]
Vinl   0.585   0.55125   0.61875
Vinh   0.765   0.73125   0.79875
[Receiver Thresholds]
Tslew_ac = 5n
Vth= 0.675
Vth_max= 0.709
Vth_min= 0.608
Vinh_ac= 0.175
Vinh_dc= 0.1
Vinl_ac= -0.175
Vinl_dc= -0.1
[Temperature Range]   25   125   -40
[Voltage Range]   1.35   1.2825   1.4175
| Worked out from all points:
|   slope of the pulldown table from 0 to 0.203 V, typ, clamps not added: 43 ohm
|   slope of the pullup table from 0 to 0.203 V, typ, clamps not added: 42 ohm
|   GND clamp passes 1 mA (typ) near -0.48 V on its own axis
|   POWER clamp passes 1 mA (typ) near -0.72 V on its own axis
|   rising waveform, R_fixture 50, V_fixture 1.35: 20-80 % time 91.2ps typ, 208ps min, 54.4ps max; typ from 0.625 V to 1.35 V
|   rising waveform, R_fixture 50, V_fixture 0: 20-80 % time 91.2ps typ, 202ps min, 54.1ps max; typ from 0 V to 0.733 V
|   falling waveform, R_fixture 50, V_fixture 1.35: 20-80 % time 91.3ps typ, 193ps min, 55.5ps max; typ from 1.35 V to 0.625 V
|   falling waveform, R_fixture 50, V_fixture 0: 20-80 % time 91.2ps typ, 197ps min, 55.2ps max; typ from 0.733 V to 0 V
[POWER_clamp]
-1.35V    224.4mA    165.8mA    358.5mA
-1.214V   157mA      115.5mA    250.8mA
-1.132V   117.8mA    86.59mA    187.7mA
-1.118V   111.4mA    81.92mA    177.3mA
-1.036V   74.26mA    55.16mA    116.8mA
-954.5mV  40.7mA     31.91mA    61.06mA
-900mV    22.42mA    19.79mA    30.14mA
-859.1mV  12.48mA    13.09mA    13.96mA
-804.5mV  4.85mA     7.084mA    4.132mA
-736.4mV  1.313mA    2.9mA      1.073mA
-627.3mV  101.6uA    577.3uA    45.9uA
0V        75.63nA    322.4nA    418.5nA
[Pulldown]
-1.35V    -13.93mA   -13.71mA   -13.45mA
-736.4mV  -12.58mA   -12.32mA   -12.19mA
-531.8mV  -11.22mA   -10.8mA    -10.99mA
-409.1mV  -9.378mA   -8.926mA   -9.416mA
1.145V    26.32mA    24.88mA    26.57mA
1.718V    39.05mA    36.49mA    39.37mA
1.923V    43.49mA    39.91mA    43.83mA
2.005V    45.12mA    40.54mA    45.58mA
2.086V    46.28mA    40.65mA    47.24mA
2.209V    46.44mA    40.1mA     48.7mA
2.373V    45.86mA    39.19mA    46.8mA
2.7V      45.54mA    36.91mA    46.74mA
[Pullup]
-1.35V    19.14mA    16.53mA    19.57mA
-981.8mV  18.13mA    16.28mA    18.23mA
-818.2mV  17.57mA    15.91mA    18.13mA
-736.4mV  16.82mA    15.4mA     17.33mA
-613.6mV  14.56mA    13.83mA    14.83mA
1.064V    -25.08mA   -24.06mA   -25.52mA
1.555V    -36.41mA   -34.6mA    -37.03mA
1.759V    -40.9mA    -38.29mA   -41.73mA
1.923V    -42.98mA   -39.67mA   -44.36mA
2.127V    -43.9mA    -40.1mA    -45.7mA
2.291V    -43.85mA   -39.69mA   -45.73mA
2.7V      -43.64mA   -37.43mA   -45.74mA
[GND_clamp]
-1.35V    -100.7mA   -81.27mA   -179.3mA
-1.241V   -77.31mA   -57.61mA   -140mA
-1.132V   -54.83mA   -36.31mA   -101.6mA
-1.05V    -39.08mA   -23.36mA   -74mA
-968.2mV  -25.28mA   -14.71mA   -48.34mA
-913.6mV  -18.13mA   -11.32mA   -33.52mA
-859.1mV  -13.28mA   -9.024mA   -22.35mA
-831.8mV  -11.61mA   -8.091mA   -18.64mA
-777.3mV  -9.078mA   -6.444mA   -14.07mA
-531.8mV  -1.871mA   -1.307mA   -3.441mA
-368.2mV  -88.76uA   -111.2uA   -158uA
1.35V     75.63nA    385.5nA    349.4nA
[Ramp]
dV/dt_f 0.43558262/91.40583p  0.40476929/0.19325305n 0.45930907/55.547329p
dV/dt_r 0.44168804/91.627517p 0.41292997/0.20360653n 0.46732083/54.369436p
R_load = 50
[Rising Waveform]
R_fixture = 50
V_fixture = 1.35
V_fixture_min = 1.2825
V_fixture_max = 1.4175
0s        624.9mV    609.4mV    653.1mV
27.79ps   624.2mV    609.3mV    746.8mV
91.18ps   623.5mV    609.3mV    1.27V
121.3ps   629.9mV    609.3mV    1.361V
145.1ps   706.4mV    609.3mV    1.388V
259.6ps   1.233V     609.2mV    1.412V
310.9ps   1.323V     608.3mV    1.414V
375.5ps   1.342V     625.6mV    1.415V
698.2ps   1.349V     1.246V     1.417V
1.053ns   1.35V      1.282V     1.417V
[Rising Waveform]
R_fixture = 50
V_fixture = 0
V_fixture_min = 0
V_fixture_max = 0
2.607ps   0V         0V         0V
31.2ps    0V         0V         91.09mV
95.89ps   0V         0V         628mV
124ps     0V         0V         716.1mV
150.3ps   76.77mV    0V         747.6mV
264.9ps   611.5mV    0V         771.2mV
314ps     703.5mV    0V         772.7mV
389.8ps   726.1mV    18.78mV    773.9mV
711.8ps   731.9mV    644.7mV    775.5mV
1.055ns   733mV      684.9mV    775.7mV
[Falling Waveform]
R_fixture = 50
V_fixture = 1.35
V_fixture_min = 1.2825
V_fixture_max = 1.4175
0s        1.35V      1.282V     1.417V
20.88ps   1.35V      1.283V     1.408V
35.66ps   1.35V      1.283V     1.348V
105.4ps   1.35V      1.283V     797mV
160.7ps   1.296V     1.283V     681.5mV
279.8ps   751.5mV    1.283V     657.7mV
330.8ps   656mV      1.282V     656.1mV
437.1ps   630.7mV    1.262V     654.2mV
748.3ps   626.2mV    650.7mV    652.7mV
1.053ns   624.9mV    609.4mV    652.5mV
[Falling Waveform]
R_fixture = 50
V_fixture = 0
V_fixture_min = 0
V_fixture_max = 0
2.607ps   733mV      684.9mV    775.7mV
33.13ps   733.2mV    685mV      698.6mV
101ps     732.8mV    685mV      146.5mV
136.9ps   727.2mV    685mV      48.51mV
156.9ps   673.5mV    685mV      28.46mV
275.3ps   122.3mV    685mV      4.697mV
325.9ps   29.81mV    684.8mV    2.976mV
425.7ps   5.882mV    663.1mV    0V
732.2ps   0V         40.9mV     0V
1.055ns   0V         0V         0V
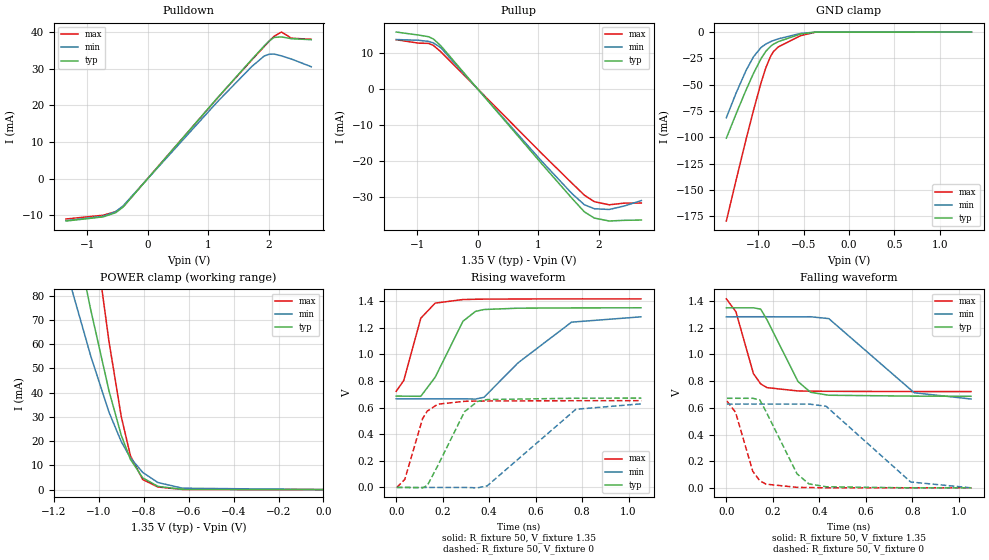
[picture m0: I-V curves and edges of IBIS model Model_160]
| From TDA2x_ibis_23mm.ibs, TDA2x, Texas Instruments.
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| Model based on original model for DDR_SEIOPB_H
|   Sub model SR011_DRV48_1P35
[model]   Model_160
|[Description]  [1.35V-I/O-X-X]
|   , ,
|[Input Load]
|[Output Drive]
|Voltage   1.35V
|Mode   I/O
Model_type   I/O
Polarity   Non-Inverting
Enable   Active-Low
Vinl =  0.585
Vinh =  0.765
Cref =  15.0000pF
Rref =  100.0000M
Vref =  0V
Vmeas =  0.675
C_comp   2p   2p   2p
[Model Spec]
Vinl   0.585   0.55125   0.61875
Vinh   0.765   0.73125   0.79875
[Receiver Thresholds]
Tslew_ac = 5n
Vth= 0.675
Vth_max= 0.709
Vth_min= 0.608
Vinh_ac= 0.175
Vinh_dc= 0.1
Vinl_ac= -0.175
Vinl_dc= -0.1
[Temperature Range]   25   125   -40
[Voltage Range]   1.35   1.2825   1.4175
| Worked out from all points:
|   slope of the pulldown table from 0 to 0.203 V, typ, clamps not added: 51.5 ohm
|   slope of the pullup table from 0 to 0.203 V, typ, clamps not added: 50.4 ohm
|   GND clamp passes 1 mA (typ) near -0.48 V on its own axis
|   POWER clamp passes 1 mA (typ) near -0.72 V on its own axis
|   rising waveform, R_fixture 50, V_fixture 1.35: 20-80 % time 113ps typ, 274ps min, 66.1ps max; typ from 0.687 V to 1.35 V
|   rising waveform, R_fixture 50, V_fixture 0: 20-80 % time 112ps typ, 268ps min, 64.7ps max; typ from 0 V to 0.671 V
|   falling waveform, R_fixture 50, V_fixture 1.35: 20-80 % time 113ps typ, 256ps min, 66.7ps max; typ from 1.35 V to 0.687 V
|   falling waveform, R_fixture 50, V_fixture 0: 20-80 % time 113ps typ, 262ps min, 64.2ps max; typ from 0.671 V to 0 V
[POWER_clamp]
-1.35V    224.4mA    165.8mA    358.5mA
-1.214V   157mA      115.5mA    250.8mA
-1.132V   117.8mA    86.59mA    187.7mA
-1.118V   111.4mA    81.92mA    177.3mA
-1.036V   74.26mA    55.16mA    116.8mA
-954.5mV  40.7mA     31.91mA    61.06mA
-900mV    22.42mA    19.79mA    30.14mA
-859.1mV  12.48mA    13.09mA    13.96mA
-804.5mV  4.85mA     7.084mA    4.132mA
-736.4mV  1.313mA    2.9mA      1.073mA
-627.3mV  101.6uA    577.3uA    45.9uA
0V        75.63nA    322.4nA    418.5nA
[Pulldown]
-1.35V    -11.61mA   -11.5mA    -11.06mA
-736.4mV  -10.48mA   -10.33mA   -10.03mA
-531.8mV  -9.35mA    -9.062mA   -9.043mA
-409.1mV  -7.817mA   -7.49mA    -7.751mA
1.145V    21.94mA    20.88mA    21.88mA
1.718V    32.55mA    30.62mA    32.41mA
1.923V    36.25mA    33.48mA    36.08mA
2.005V    37.61mA    33.98mA    37.53mA
2.086V    38.57mA    34.03mA    38.89mA
2.209V    38.7mA     33.51mA    40.04mA
2.373V    38.22mA    32.66mA    38.36mA
2.7V      37.95mA    30.56mA    38.05mA
[Pullup]
-1.35V    15.95mA    13.86mA    13.81mA
-981.8mV  15.11mA    13.66mA    12.86mA
-818.2mV  14.65mA    13.35mA    12.79mA
-736.4mV  14.02mA    12.92mA    12.23mA
-613.6mV  12.13mA    11.6mA     10.47mA
1.064V    -20.91mA   -20.19mA   -18.01mA
1.555V    -30.35mA   -29.03mA   -26.14mA
1.759V    -34.1mA    -32.12mA   -29.45mA
1.923V    -35.82mA   -33.22mA   -31.26mA
2.168V    -36.64mA   -33.43mA   -32.13mA
2.414V    -36.45mA   -32.48mA   -31.67mA
2.7V      -36.37mA   -30.94mA   -31.63mA
[GND_clamp]
-1.35V    -100.7mA   -81.27mA   -179.3mA
-1.241V   -77.31mA   -57.61mA   -140mA
-1.132V   -54.83mA   -36.31mA   -101.6mA
-1.05V    -39.08mA   -23.36mA   -74mA
-968.2mV  -25.28mA   -14.71mA   -48.34mA
-913.6mV  -18.13mA   -11.32mA   -33.52mA
-859.1mV  -13.28mA   -9.024mA   -22.35mA
-831.8mV  -11.61mA   -8.091mA   -18.64mA
-777.3mV  -9.078mA   -6.444mA   -14.07mA
-531.8mV  -1.871mA   -1.307mA   -3.441mA
-368.2mV  -88.76uA   -111.2uA   -158uA
1.35V     75.63nA    385.5nA    349.4nA
[Ramp]
dV/dt_f 0.39858485/0.11299527n 0.37079865/0.25730624n 0.41791344/66.775518p
dV/dt_r 0.40474272/0.11278724n 0.37913037/0.27016627n 0.39238656/64.912496p
R_load = 50
[Rising Waveform]
R_fixture = 50
V_fixture = 1.35
V_fixture_min = 1.2825
V_fixture_max = 1.4175
0s        686.6mV    666.1mV    722.5mV
32.45ps   685.9mV    666mV      803.4mV
105.9ps   684.8mV    666mV      1.272V
167.7ps   828.4mV    666.1mV    1.385V
287.4ps   1.249V     665.9mV    1.412V
341.2ps   1.323V     664mV      1.414V
377.9ps   1.337V     677.4mV    1.415V
524.2ps   1.347V     936.1mV    1.416V
754.4ps   1.349V     1.242V     1.417V
1.053ns   1.35V      1.282V     1.417V
[Rising Waveform]
R_fixture = 50
V_fixture = 0
V_fixture_min = 0
V_fixture_max = 0
2.649ps   0V         0V         0V
36.95ps   0V         0V         60.29mV
113.8ps   -3.076mV   0V         518.9mV
134.2ps   15.41mV    0V         574.6mV
178.9ps   163.7mV    0V         625.4mV
294.2ps   569.7mV    0V         647.3mV
349.9ps   646.1mV    -3.001mV   649mV
391.5ps   660.3mV    11.69mV    649.8mV
773ps     670.5mV    587.2mV    651.7mV
1.055ns   671.4mV    628.3mV    651.8mV
[Falling Waveform]
R_fixture = 50
V_fixture = 1.35
V_fixture_min = 1.2825
V_fixture_max = 1.4175
0s        1.35V      1.282V     1.417V
41.14ps   1.35V      1.283V     1.321V
116.5ps   1.35V      1.283V     856.9mV
147.9ps   1.34V      1.283V     779.1mV
175ps     1.26V      1.283V     751.4mV
308.5ps   797.1mV    1.282V     726.5mV
362.2ps   716.6mV    1.283V     725mV
441ps     694.4mV    1.269V     723.7mV
808.6ps   687.7mV    713mV      722mV
1.053ns   686.6mV    666.1mV    721.8mV
[Falling Waveform]
R_fixture = 50
V_fixture = 0
V_fixture_min = 0
V_fixture_max = 0
2.649ps   671.4mV    628.3mV    650.9mV
39.77ps   671.6mV    628.3mV    565.9mV
113.6ps   671.5mV    628.4mV    124.7mV
143.6ps   660.2mV    628.4mV    54mV
170.5ps   573.2mV    628.3mV    27.67mV
304.2ps   105.4mV    628.2mV    3.736mV
355.5ps   29.7mV     628.4mV    2.316mV
429.4ps   8.083mV    611.5mV    0V
793.5ps   0V         43.77mV    0V
1.055ns   0V         0V         0V
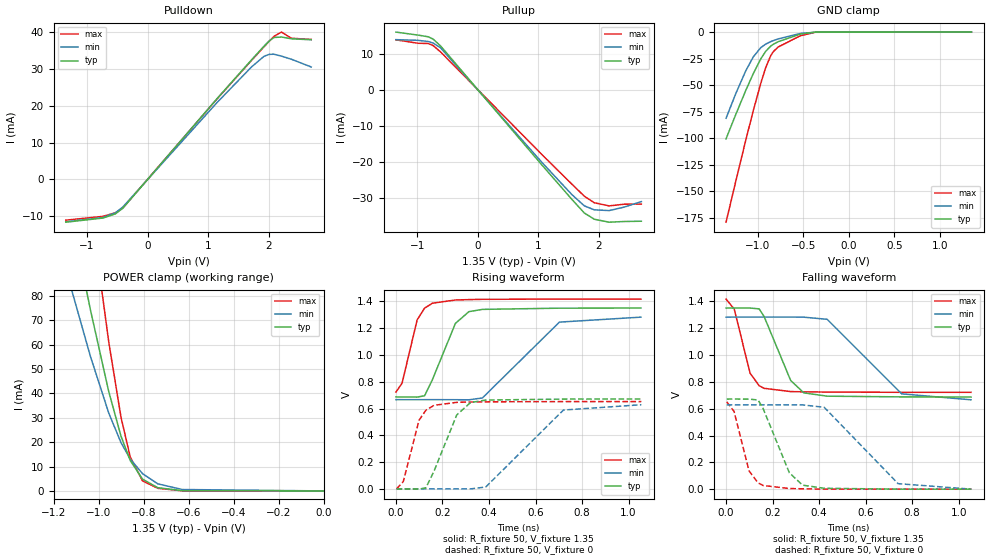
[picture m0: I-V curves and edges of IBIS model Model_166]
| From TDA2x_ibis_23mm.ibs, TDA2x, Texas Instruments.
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| Model based on original model for DDR_SEIOPB_H
|   Sub model SR001_DRV48_1P35
[model]   Model_166
|[Description]  [1.35V-I/O-X-X]
|   , ,
|[Input Load]
|[Output Drive]
|Voltage   1.35V
|Mode   I/O
Model_type   I/O
Polarity   Non-Inverting
Enable   Active-Low
Vinl =  0.585
Vinh =  0.765
Cref =  15.0000pF
Rref =  100.0000M
Vref =  0V
Vmeas =  0.675
C_comp   2p   2p   2p
[Model Spec]
Vinl   0.585   0.55125   0.61875
Vinh   0.765   0.73125   0.79875
[Receiver Thresholds]
Tslew_ac = 5n
Vth= 0.675
Vth_max= 0.709
Vth_min= 0.608
Vinh_ac= 0.175
Vinh_dc= 0.1
Vinl_ac= -0.175
Vinl_dc= -0.1
[Temperature Range]   25   125   -40
[Voltage Range]   1.35   1.2825   1.4175
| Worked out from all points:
|   slope of the pulldown table from 0 to 0.203 V, typ, clamps not added: 51.5 ohm
|   slope of the pullup table from 0 to 0.203 V, typ, clamps not added: 50.4 ohm
|   GND clamp passes 1 mA (typ) near -0.48 V on its own axis
|   POWER clamp passes 1 mA (typ) near -0.72 V on its own axis
|   rising waveform, R_fixture 50, V_fixture 1.35: 20-80 % time 92.8ps typ, 227ps min, 58.7ps max; typ from 0.687 V to 1.35 V
|   rising waveform, R_fixture 50, V_fixture 0: 20-80 % time 92.9ps typ, 221ps min, 57.8ps max; typ from 0 V to 0.671 V
|   falling waveform, R_fixture 50, V_fixture 1.35: 20-80 % time 94ps typ, 211ps min, 59ps max; typ from 1.35 V to 0.687 V
|   falling waveform, R_fixture 50, V_fixture 0: 20-80 % time 93.7ps typ, 215ps min, 56.8ps max; typ from 0.671 V to 0 V
[POWER_clamp]
-1.35V    224.4mA    165.8mA    358.5mA
-1.214V   157mA      115.5mA    250.8mA
-1.132V   117.8mA    86.59mA    187.7mA
-1.118V   111.4mA    81.92mA    177.3mA
-1.036V   74.26mA    55.16mA    116.8mA
-954.5mV  40.7mA     31.91mA    61.06mA
-900mV    22.42mA    19.79mA    30.14mA
-859.1mV  12.48mA    13.09mA    13.96mA
-804.5mV  4.85mA     7.084mA    4.132mA
-736.4mV  1.313mA    2.9mA      1.073mA
-627.3mV  101.6uA    577.3uA    45.9uA
0V        75.63nA    322.4nA    418.5nA
[Pulldown]
-1.35V    -11.61mA   -11.5mA    -11.06mA
-736.4mV  -10.48mA   -10.33mA   -10.03mA
-531.8mV  -9.35mA    -9.062mA   -9.043mA
-409.1mV  -7.817mA   -7.49mA    -7.751mA
1.145V    21.94mA    20.88mA    21.88mA
1.718V    32.55mA    30.62mA    32.41mA
1.923V    36.25mA    33.48mA    36.08mA
2.005V    37.61mA    33.98mA    37.53mA
2.086V    38.57mA    34.03mA    38.89mA
2.209V    38.7mA     33.51mA    40.04mA
2.373V    38.22mA    32.66mA    38.36mA
2.7V      37.95mA    30.56mA    38.05mA
[Pullup]
-1.35V    15.95mA    13.86mA    13.81mA
-981.8mV  15.11mA    13.66mA    12.86mA
-818.2mV  14.65mA    13.35mA    12.79mA
-736.4mV  14.02mA    12.92mA    12.23mA
-613.6mV  12.13mA    11.6mA     10.47mA
1.064V    -20.91mA   -20.19mA   -18.01mA
1.555V    -30.35mA   -29.03mA   -26.14mA
1.759V    -34.1mA    -32.12mA   -29.45mA
1.923V    -35.82mA   -33.22mA   -31.26mA
2.168V    -36.64mA   -33.43mA   -32.13mA
2.414V    -36.45mA   -32.48mA   -31.67mA
2.7V      -36.37mA   -30.94mA   -31.63mA
[GND_clamp]
-1.35V    -100.7mA   -81.27mA   -179.3mA
-1.241V   -77.31mA   -57.61mA   -140mA
-1.132V   -54.83mA   -36.31mA   -101.6mA
-1.05V    -39.08mA   -23.36mA   -74mA
-968.2mV  -25.28mA   -14.71mA   -48.34mA
-913.6mV  -18.13mA   -11.32mA   -33.52mA
-859.1mV  -13.28mA   -9.024mA   -22.35mA
-831.8mV  -11.61mA   -8.091mA   -18.64mA
-777.3mV  -9.078mA   -6.444mA   -14.07mA
-531.8mV  -1.871mA   -1.307mA   -3.441mA
-368.2mV  -88.76uA   -111.2uA   -158uA
1.35V     75.63nA    385.5nA    349.4nA
[Ramp]
dV/dt_f 0.39854958/94.087652p 0.37077122/0.21152455n 0.41784304/59.045388p
dV/dt_r 0.40474128/93.285921p 0.37901664/0.22295615n  0.3926236/57.955773p
R_load = 50
[Rising Waveform]
R_fixture = 50
V_fixture = 1.35
V_fixture_min = 1.2825
V_fixture_max = 1.4175
0s        686.6mV    666.1mV    722.5mV
26.37ps   685.9mV    666mV      788.9mV
91.28ps   685.3mV    666mV      1.262V
123.2ps   695mV      666mV      1.349V
156.7ps   814.6mV    666.1mV    1.386V
255.5ps   1.235V     665.8mV    1.41V
313.7ps   1.323V     665mV      1.413V
371.7ps   1.34V      678.7mV    1.415V
702.8ps   1.349V     1.245V     1.417V
1.053ns   1.35V      1.282V     1.417V
[Rising Waveform]
R_fixture = 50
V_fixture = 0
V_fixture_min = 0
V_fixture_max = 0
2.829ps   0V         0V         0V
31.74ps   0V         0V         55.39mV
99.44ps   -2.031mV   0V         512.6mV
129.1ps   9.082mV    0V         587.9mV
163.6ps   131.6mV    0V         623.7mV
261.5ps   552.4mV    0V         646.1mV
320.9ps   644.6mV    0V         648.6mV
386.1ps   663.2mV    14.07mV    649.9mV
719.9ps   670.3mV    588.6mV    651.6mV
1.055ns   671.4mV    628.3mV    651.8mV
[Falling Waveform]
R_fixture = 50
V_fixture = 1.35
V_fixture_min = 1.2825
V_fixture_max = 1.4175
0s        1.35V      1.282V     1.417V
35.25ps   1.35V      1.283V     1.342V
103.3ps   1.35V      1.283V     864.6mV
142.3ps   1.344V     1.283V     771.4mV
163.6ps   1.287V     1.283V     751.6mV
277.6ps   810.8mV    1.283V     727.5mV
334.2ps   717.9mV    1.282V     725.5mV
434.9ps   693.1mV    1.266V     723.7mV
754.9ps   687.9mV    710.5mV    722mV
1.053ns   686.6mV    666.1mV    721.8mV
[Falling Waveform]
R_fixture = 50
V_fixture = 0
V_fixture_min = 0
V_fixture_max = 0
2.829ps   671.4mV    628.3mV    651mV
34.27ps   671.6mV    628.3mV    580mV
98.91ps   671.1mV    628.4mV    136mV
137.7ps   664.8mV    628.4mV    46.65mV
159.3ps   601.4mV    628.4mV    27.52mV
272.1ps   121.9mV    628.4mV    4.663mV
329ps     29.93mV    628.1mV    2.714mV
421.9ps   6.686mV    610.2mV    0V
739.8ps   0V         41.01mV    0V
1.055ns   0V         0V         0V
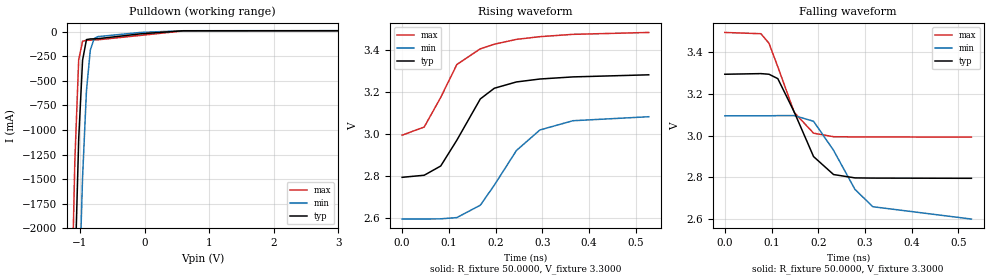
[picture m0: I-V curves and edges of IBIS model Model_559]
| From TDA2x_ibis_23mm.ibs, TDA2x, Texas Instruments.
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| Model based on original model for HDMITXPHY
|   Sub model ibis_tmdsp
[model]   Model_559
|[Description]  [1.8000V-OPEN_DRAIN-X-X]
|   , ,
|[Input Load]
|[Output Drive]
|Voltage   1.8000V
|Mode   OPEN_DRAIN
Model_type   Open_drain
Polarity   Non-Inverting
Enable   Active-High
Vmeas =   3.0500V
C_comp   0.7000pF   0.3000pF   1.0000pF
[Temperature Range]   25.0000   0.1250k   -40.0000
[Voltage Range]   1.8000V   1.6700V   1.9800V
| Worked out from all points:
|   slope of the pulldown table from 0 to 0.27 V, typ, clamps not added: 15.5 ohm
|   rising waveform, R_fixture 50.0000, V_fixture 3.3000: 20-80 % time 77.1ps typ, 92.9ps min, 82.9ps max; typ from 2.79 V to 3.28 V
|   falling waveform, R_fixture 50.0000, V_fixture 3.3000: 20-80 % time 56.8ps typ, 77.9ps min, 49.1ps max; typ from 3.29 V to 2.8 V
[Pulldown]
-1.8V     -29.98A    -32.49A    -29.86A
-1.14V    -4.342A    -6.258A    -3.096A
-1.08V    -2.528A    -4.418A    -1.321A
-1.02V    -1.091A    -2.791A    -285mA
-960mV    -289.5mA   -1.48A     -97.47mA
-900mV    -80.58mA   -601.2mA   -87.77mA
-840mV    -73.73mA   -185.7mA   -86.71mA
-780mV    -72.92mA   -68.94mA   -82.73mA
-720mV    -71.15mA   -49.82mA   -82.25mA
-60mV     -21.63mA   -7.457mA   -37.55mA
600mV     9.513mA    9.572mA    8.084mA
3.6V      10.1mA     10.09mA    10.13mA
[Ramp]
dV/dt_r   0.2928/77.4327p   0.2925/95.2986p   0.2944/76.9568p
dV/dt_f   0.2989/58.8936p   0.2960/80.0923p   0.3004/51.2049p
R_load =   50.0000
[Rising Waveform]
R_fixture=   50.0000
V_fixture=   3.3000
V_fixture_min=  3.1000
V_fixture_max=  3.5000
0s        2.794V     2.595V     2.995V
47.3ps    2.804V     2.595V     3.034V
82.58ps   2.848V     2.596V     3.175V
117.1ps   2.971V     2.602V     3.332V
167.4ps   3.168V     2.661V     3.407V
197.4ps   3.219V     2.757V     3.429V
244.7ps   3.249V     2.922V     3.452V
295ps     3.263V     3.02V      3.465V
365.6ps   3.273V     3.064V     3.476V
527.8ps   3.283V     3.083V     3.485V
[Falling Waveform]
R_fixture=   50.0000
V_fixture=   3.3000
V_fixture_min=  3.1000
V_fixture_max=  3.5000
0s        3.294V     3.095V     3.494V
77.33ps   3.297V     3.095V     3.488V
94.59ps   3.294V     3.095V     3.442V
113.4ps   3.273V     3.096V     3.33V
148.6ps   3.113V     3.096V     3.111V
189.9ps   2.9V       3.069V     3.012V
232.7ps   2.814V     2.93V      2.995V
278.5ps   2.798V     2.743V     2.994V
316.8ps   2.797V     2.66V      2.994V
527.8ps   2.796V     2.601V     2.993V
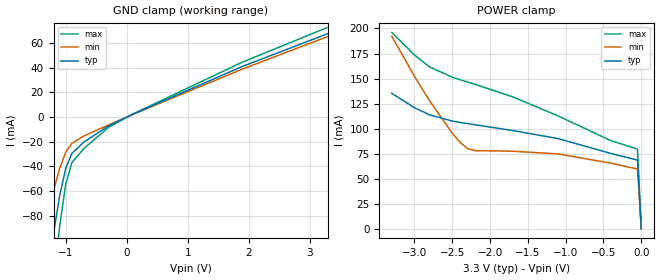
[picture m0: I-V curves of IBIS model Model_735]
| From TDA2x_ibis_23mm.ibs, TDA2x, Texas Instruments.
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| Model based on original model for USB2PHYCORE_HMAV10GS80
|   Sub model hsrx
[model]   Model_735
|[Description]  [3.3V-INPUT-X-X]
|   , ,
|[Input Load]
|[Output Drive]
|Voltage   3.3V
|Mode   INPUT
Model_type   Input
C_comp   7.0000pF   7.0000pF   7.0000pF
Vinl= 0.2
Vinh= 0.22
[Temperature Range]   27.0000   0.1250k   -40.0000
[Voltage Range]   3.3V   3.0V   3.6V
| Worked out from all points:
|   GND clamp passes 1 mA (typ) near -0.04 V on its own axis
|   POWER clamp passes 1 mA (typ) near -0.00 V on its own axis
[GND_clamp]
-3.3V     -863.9mA   -560mA     -1.286A
-1.4V     -162.5mA   -102.1mA   -239.7mA
-1.3V     -127.6mA   -80.17mA   -186.7mA
-1.2V     -94.17mA   -59.63mA   -135.6mA
-1.1V     -64.09mA   -41.67mA   -88.9mA
-1V       -41.57mA   -28.51mA   -54.46mA
-900mV    -29.55mA   -21.35mA   -37.03mA
-700mV    -20.16mA   -15.21mA   -25.39mA
-300mV    -7.209mA   -6.419mA   -8.37mA
100mV     2.254mA    2.119mA    2.45mA
1.9V      41.08mA    38.92mA    44.56mA
3.3V      67.65mA    65.35mA    72.78mA
[POWER_clamp]
-3.3V     135.2mA    192.2mA    196.1mA
-3V       120.8mA    152.2mA    173.5mA
-2.8V     113.7mA    127.7mA    161.6mA
-2.5V     107.5mA    95.4mA     151.3mA
-2.4V     106.2mA    86.49mA    148.9mA
-2.3V     105mA      80.13mA    146.6mA
-2.2V     103.8mA    77.99mA    144.3mA
-1.7V     98.05mA    77.38mA    131.7mA
-1.1V     89.98mA    74.68mA    112.6mA
-400mV    75.11mA    65.35mA    87.9mA
-50mV     68.49mA    59.62mA    79.53mA
0V        0A         0A         0A
